VERSION 5.7 ;
  NOWIREEXTENSIONATPIN ON ;
  DIVIDERCHAR "/" ;
  BUSBITCHARS "[]" ;
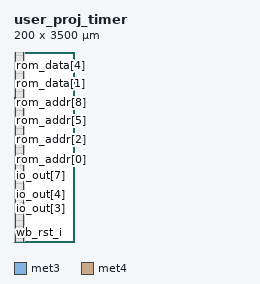
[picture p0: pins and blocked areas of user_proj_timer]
MACRO user_proj_timer
  CLASS BLOCK ;
  FOREIGN user_proj_timer ;
  ORIGIN 0.000 0.000 ;
  SIZE 200.000 BY 3500.000 ;
  PIN io_out[0]
    DIRECTION OUTPUT ;
    USE SIGNAL ;
    ANTENNADIFFAREA 0.445500 ;
    PORT
      LAYER met3 ;
        RECT 0.000 281.560 4.000 282.160 ;
    END
  END io_out[0]
  PIN io_out[10]
    DIRECTION OUTPUT ;
    USE SIGNAL ;
    ANTENNADIFFAREA 0.445500 ;
    PORT
      LAYER met3 ;
        RECT 0.000 1410.360 4.000 1410.960 ;
    END
  END io_out[10]
  PIN io_out[1]
    DIRECTION OUTPUT ;
    USE SIGNAL ;
    ANTENNADIFFAREA 0.445500 ;
    PORT
      LAYER met3 ;
        RECT 0.000 394.440 4.000 395.040 ;
    END
  END io_out[1]
  PIN io_out[2]
    DIRECTION OUTPUT ;
    USE SIGNAL ;
    ANTENNADIFFAREA 0.445500 ;
    PORT
      LAYER met3 ;
        RECT 0.000 507.320 4.000 507.920 ;
    END
  END io_out[2]
  PIN io_out[3]
    DIRECTION OUTPUT ;
    USE SIGNAL ;
    ANTENNADIFFAREA 0.445500 ;
    PORT
      LAYER met3 ;
        RECT 0.000 620.200 4.000 620.800 ;
    END
  END io_out[3]
  PIN io_out[4]
    DIRECTION OUTPUT ;
    USE SIGNAL ;
    ANTENNADIFFAREA 0.445500 ;
    PORT
      LAYER met3 ;
        RECT 0.000 733.080 4.000 733.680 ;
    END
  END io_out[4]
  PIN io_out[5]
    DIRECTION OUTPUT ;
    USE SIGNAL ;
    ANTENNADIFFAREA 0.445500 ;
    PORT
      LAYER met3 ;
        RECT 0.000 845.960 4.000 846.560 ;
    END
  END io_out[5]
  PIN io_out[6]
    DIRECTION OUTPUT ;
    USE SIGNAL ;
    ANTENNADIFFAREA 0.445500 ;
    PORT
      LAYER met3 ;
        RECT 0.000 958.840 4.000 959.440 ;
    END
  END io_out[6]
  PIN io_out[7]
    DIRECTION OUTPUT ;
    USE SIGNAL ;
    ANTENNADIFFAREA 0.445500 ;
    PORT
      LAYER met3 ;
        RECT 0.000 1071.720 4.000 1072.320 ;
    END
  END io_out[7]
  PIN io_out[8]
    DIRECTION OUTPUT ;
    USE SIGNAL ;
    ANTENNADIFFAREA 0.445500 ;
    PORT
      LAYER met3 ;
        RECT 0.000 1184.600 4.000 1185.200 ;
    END
  END io_out[8]
  PIN io_out[9]
    DIRECTION OUTPUT ;
    USE SIGNAL ;
    ANTENNADIFFAREA 0.445500 ;
    PORT
      LAYER met3 ;
        RECT 0.000 1297.480 4.000 1298.080 ;
    END
  END io_out[9]
  PIN rom_addr[0]
    DIRECTION OUTPUT ;
    USE SIGNAL ;
    ANTENNADIFFAREA 0.445500 ;
    PORT
      LAYER met3 ;
        RECT 0.000 1523.240 4.000 1523.840 ;
    END
  END rom_addr[0]
  PIN rom_addr[1]
    DIRECTION OUTPUT ;
    USE SIGNAL ;
    ANTENNADIFFAREA 0.445500 ;
    PORT
      LAYER met3 ;
        RECT 0.000 1636.120 4.000 1636.720 ;
    END
  END rom_addr[1]
  PIN rom_addr[2]
    DIRECTION OUTPUT ;
    USE SIGNAL ;
    ANTENNADIFFAREA 0.445500 ;
    PORT
      LAYER met3 ;
        RECT 0.000 1749.000 4.000 1749.600 ;
    END
  END rom_addr[2]
  PIN rom_addr[3]
    DIRECTION OUTPUT ;
    USE SIGNAL ;
    ANTENNADIFFAREA 0.445500 ;
    PORT
      LAYER met3 ;
        RECT 0.000 1861.880 4.000 1862.480 ;
    END
  END rom_addr[3]
  PIN rom_addr[4]
    DIRECTION OUTPUT ;
    USE SIGNAL ;
    PORT
      LAYER met3 ;
        RECT 0.000 1974.760 4.000 1975.360 ;
    END
  END rom_addr[4]
  PIN rom_addr[5]
    DIRECTION OUTPUT ;
    USE SIGNAL ;
    PORT
      LAYER met3 ;
        RECT 0.000 2087.640 4.000 2088.240 ;
    END
  END rom_addr[5]
  PIN rom_addr[6]
    DIRECTION OUTPUT ;
    USE SIGNAL ;
    PORT
      LAYER met3 ;
        RECT 0.000 2200.520 4.000 2201.120 ;
    END
  END rom_addr[6]
  PIN rom_addr[7]
    DIRECTION OUTPUT ;
    USE SIGNAL ;
    PORT
      LAYER met3 ;
        RECT 0.000 2313.400 4.000 2314.000 ;
    END
  END rom_addr[7]
  PIN rom_addr[8]
    DIRECTION OUTPUT ;
    USE SIGNAL ;
    PORT
      LAYER met3 ;
        RECT 0.000 2426.280 4.000 2426.880 ;
    END
  END rom_addr[8]
  PIN rom_addr[9]
    DIRECTION OUTPUT ;
    USE SIGNAL ;
    PORT
      LAYER met3 ;
        RECT 0.000 2539.160 4.000 2539.760 ;
    END
  END rom_addr[9]
  PIN rom_data[0]
    DIRECTION INPUT ;
    USE SIGNAL ;
    ANTENNAGATEAREA 0.593700 ;
    ANTENNADIFFAREA 0.434700 ;
    PORT
      LAYER met3 ;
        RECT 0.000 2652.040 4.000 2652.640 ;
    END
  END rom_data[0]
  PIN rom_data[1]
    DIRECTION INPUT ;
    USE SIGNAL ;
    ANTENNAGATEAREA 1.424700 ;
    ANTENNADIFFAREA 0.434700 ;
    PORT
      LAYER met3 ;
        RECT 0.000 2764.920 4.000 2765.520 ;
    END
  END rom_data[1]
  PIN rom_data[2]
    DIRECTION INPUT ;
    USE SIGNAL ;
    ANTENNAGATEAREA 1.424700 ;
    ANTENNADIFFAREA 0.434700 ;
    PORT
      LAYER met3 ;
        RECT 0.000 2877.800 4.000 2878.400 ;
    END
  END rom_data[2]
  PIN rom_data[3]
    DIRECTION INPUT ;
    USE SIGNAL ;
    ANTENNAGATEAREA 1.424700 ;
    ANTENNADIFFAREA 0.434700 ;
    PORT
      LAYER met3 ;
        RECT 0.000 2990.680 4.000 2991.280 ;
    END
  END rom_data[3]
  PIN rom_data[4]
    DIRECTION INPUT ;
    USE SIGNAL ;
    ANTENNAGATEAREA 1.424700 ;
    ANTENNADIFFAREA 0.434700 ;
    PORT
      LAYER met3 ;
        RECT 0.000 3103.560 4.000 3104.160 ;
    END
  END rom_data[4]
  PIN rom_data[5]
    DIRECTION INPUT ;
    USE SIGNAL ;
    ANTENNAGATEAREA 1.424700 ;
    ANTENNADIFFAREA 0.434700 ;
    PORT
      LAYER met3 ;
        RECT 0.000 3216.440 4.000 3217.040 ;
    END
  END rom_data[5]
  PIN rom_data[6]
    DIRECTION INPUT ;
    USE SIGNAL ;
    ANTENNAGATEAREA 1.424700 ;
    ANTENNADIFFAREA 0.434700 ;
    PORT
      LAYER met3 ;
        RECT 0.000 3329.320 4.000 3329.920 ;
    END
  END rom_data[6]
  PIN rom_data[7]
    DIRECTION INPUT ;
    USE SIGNAL ;
    PORT
      LAYER met3 ;
        RECT 0.000 3442.200 4.000 3442.800 ;
    END
  END rom_data[7]
  PIN vccd1
    DIRECTION INOUT ;
    USE POWER ;
    PORT
      LAYER met4 ;
        RECT 21.040 10.640 22.640 3487.280 ;
    END
    PORT
      LAYER met4 ;
        RECT 174.640 10.640 176.240 3487.280 ;
    END
  END vccd1
  PIN vssd1
    DIRECTION INOUT ;
    USE GROUND ;
    PORT
      LAYER met4 ;
        RECT 24.340 10.640 25.940 3487.280 ;
    END
    PORT
      LAYER met4 ;
        RECT 177.940 10.640 179.540 3487.280 ;
    END
  END vssd1
  PIN wb_clk_i
    DIRECTION INPUT ;
    USE SIGNAL ;
    ANTENNAGATEAREA 1.286700 ;
    ANTENNADIFFAREA 0.434700 ;
    PORT
      LAYER met3 ;
        RECT 0.000 55.800 4.000 56.400 ;
    END
  END wb_clk_i
  PIN wb_rst_i
    DIRECTION INPUT ;
    USE SIGNAL ;
    ANTENNAGATEAREA 0.682200 ;
    ANTENNADIFFAREA 0.434700 ;
    PORT
      LAYER met3 ;
        RECT 0.000 168.680 4.000 169.280 ;
    END
  END wb_rst_i
  OBS
      LAYER nwell ;
        RECT 5.330 10.795 194.310 3487.125 ;
      LAYER li1 ;
        RECT 5.520 10.795 194.120 3487.125 ;
      LAYER met1 ;
        RECT 4.210 10.640 194.120 3487.280 ;
      LAYER met2 ;
        RECT 4.230 10.695 179.510 3487.225 ;
      LAYER met3 ;
        RECT 3.990 3443.200 179.530 3487.205 ;
        RECT 4.400 3441.800 179.530 3443.200 ;
        RECT 3.990 3330.320 179.530 3441.800 ;
        RECT 4.400 3328.920 179.530 3330.320 ;
        RECT 3.990 3217.440 179.530 3328.920 ;
        RECT 4.400 3216.040 179.530 3217.440 ;
        RECT 3.990 3104.560 179.530 3216.040 ;
        RECT 4.400 3103.160 179.530 3104.560 ;
        RECT 3.990 2991.680 179.530 3103.160 ;
        RECT 4.400 2990.280 179.530 2991.680 ;
        RECT 3.990 2878.800 179.530 2990.280 ;
        RECT 4.400 2877.400 179.530 2878.800 ;
        RECT 3.990 2765.920 179.530 2877.400 ;
        RECT 4.400 2764.520 179.530 2765.920 ;
        RECT 3.990 2653.040 179.530 2764.520 ;
        RECT 4.400 2651.640 179.530 2653.040 ;
        RECT 3.990 2540.160 179.530 2651.640 ;
        RECT 4.400 2538.760 179.530 2540.160 ;
        RECT 3.990 2427.280 179.530 2538.760 ;
        RECT 4.400 2425.880 179.530 2427.280 ;
        RECT 3.990 2314.400 179.530 2425.880 ;
        RECT 4.400 2313.000 179.530 2314.400 ;
        RECT 3.990 2201.520 179.530 2313.000 ;
        RECT 4.400 2200.120 179.530 2201.520 ;
        RECT 3.990 2088.640 179.530 2200.120 ;
        RECT 4.400 2087.240 179.530 2088.640 ;
        RECT 3.990 1975.760 179.530 2087.240 ;
        RECT 4.400 1974.360 179.530 1975.760 ;
        RECT 3.990 1862.880 179.530 1974.360 ;
        RECT 4.400 1861.480 179.530 1862.880 ;
        RECT 3.990 1750.000 179.530 1861.480 ;
        RECT 4.400 1748.600 179.530 1750.000 ;
        RECT 3.990 1637.120 179.530 1748.600 ;
        RECT 4.400 1635.720 179.530 1637.120 ;
        RECT 3.990 1524.240 179.530 1635.720 ;
        RECT 4.400 1522.840 179.530 1524.240 ;
        RECT 3.990 1411.360 179.530 1522.840 ;
        RECT 4.400 1409.960 179.530 1411.360 ;
        RECT 3.990 1298.480 179.530 1409.960 ;
        RECT 4.400 1297.080 179.530 1298.480 ;
        RECT 3.990 1185.600 179.530 1297.080 ;
        RECT 4.400 1184.200 179.530 1185.600 ;
        RECT 3.990 1072.720 179.530 1184.200 ;
        RECT 4.400 1071.320 179.530 1072.720 ;
        RECT 3.990 959.840 179.530 1071.320 ;
        RECT 4.400 958.440 179.530 959.840 ;
        RECT 3.990 846.960 179.530 958.440 ;
        RECT 4.400 845.560 179.530 846.960 ;
        RECT 3.990 734.080 179.530 845.560 ;
        RECT 4.400 732.680 179.530 734.080 ;
        RECT 3.990 621.200 179.530 732.680 ;
        RECT 4.400 619.800 179.530 621.200 ;
        RECT 3.990 508.320 179.530 619.800 ;
        RECT 4.400 506.920 179.530 508.320 ;
        RECT 3.990 395.440 179.530 506.920 ;
        RECT 4.400 394.040 179.530 395.440 ;
        RECT 3.990 282.560 179.530 394.040 ;
        RECT 4.400 281.160 179.530 282.560 ;
        RECT 3.990 169.680 179.530 281.160 ;
        RECT 4.400 168.280 179.530 169.680 ;
        RECT 3.990 56.800 179.530 168.280 ;
        RECT 4.400 55.400 179.530 56.800 ;
        RECT 3.990 10.715 179.530 55.400 ;
      LAYER met4 ;
        RECT 30.655 172.215 30.985 487.385 ;
  END
END user_proj_timer
END LIBRARY

